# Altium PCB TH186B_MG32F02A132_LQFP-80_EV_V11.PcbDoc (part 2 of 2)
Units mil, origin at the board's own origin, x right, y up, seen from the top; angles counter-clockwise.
Board outline 4370.08 x 2637.8 mil, 2 copper layers (Top Layer, Bottom Layer); 115 components, 136 nets, 568 pads, 235 vias.

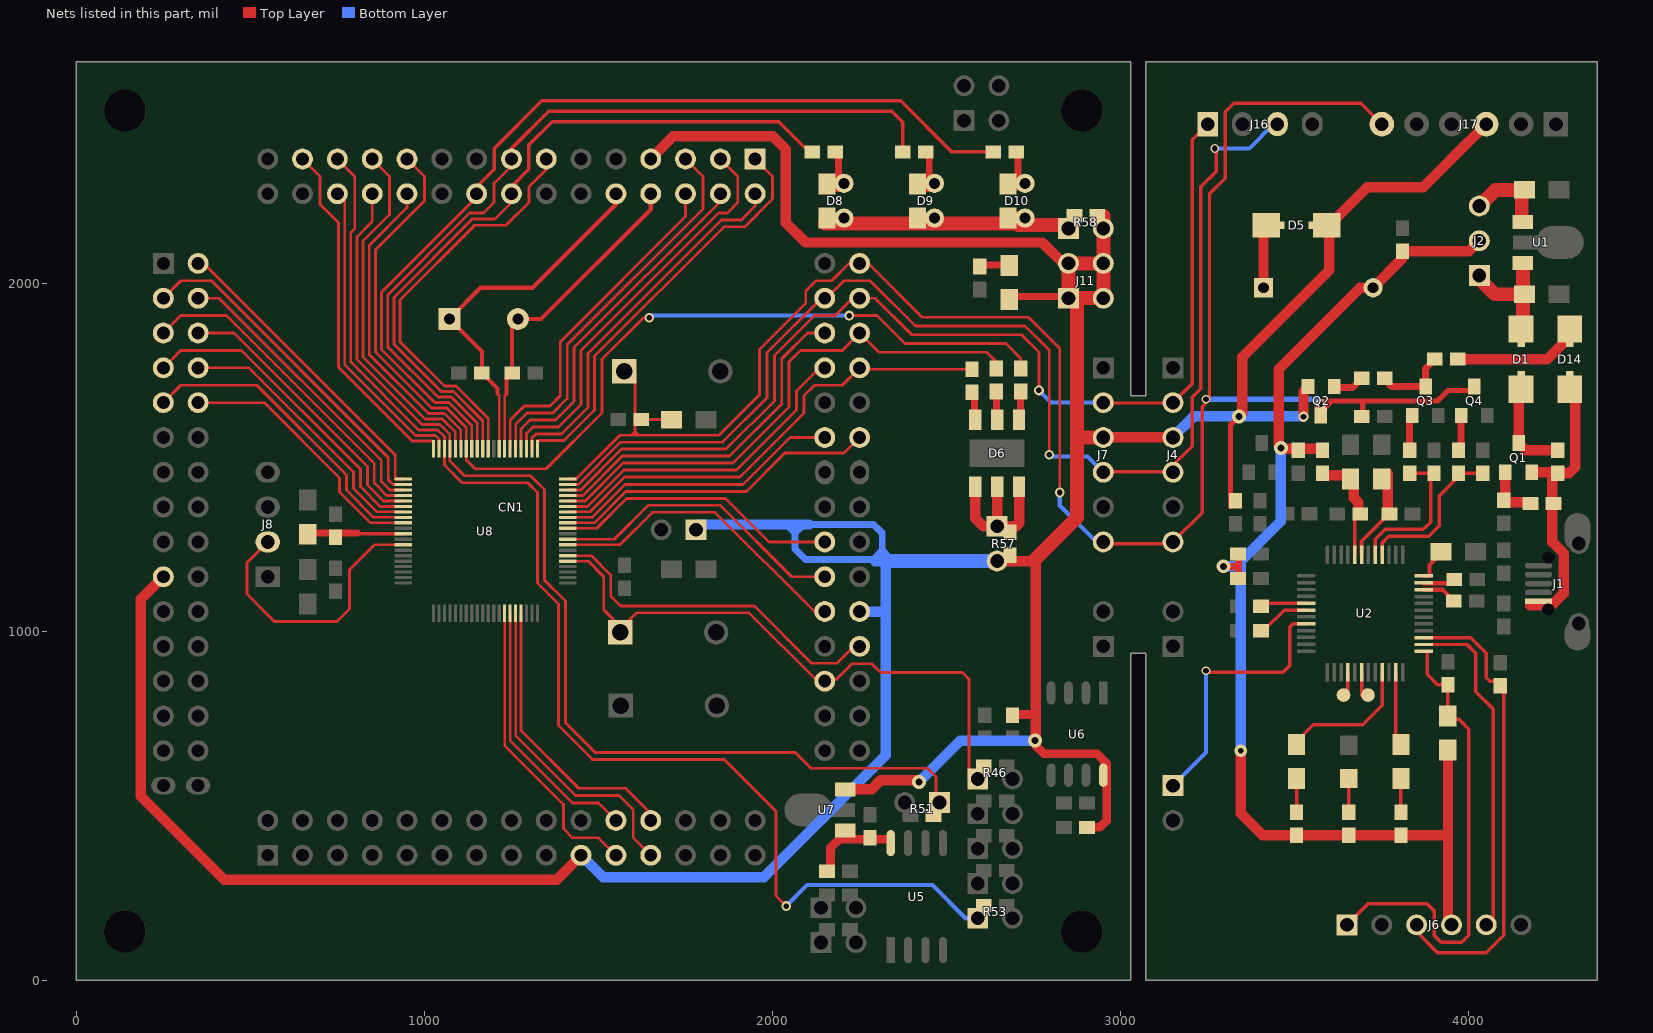
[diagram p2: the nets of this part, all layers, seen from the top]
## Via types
v1: diameter 30, hole 12, Top Layer to Bottom Layer, tented both sides, 105 vias
v2: diameter 20, hole 12, Top Layer to Bottom Layer, tented both sides, 76 vias
v3: diameter 25, hole 12, Top Layer to Bottom Layer, tented both sides, 33 vias
v4: diameter 28, hole 16, Top Layer to Bottom Layer, tented both sides, 8 vias
v5: diameter 40, hole 20, Top Layer to Bottom Layer, tented both sides, 5 vias
v6: diameter 25, hole 16, Top Layer to Bottom Layer, tented both sides, 4 vias
v7: diameter 30, hole 16, Top Layer to Bottom Layer, tented both sides, 2 vias
v8: diameter 35, hole 16, Top Layer to Bottom Layer, tented both sides, 1 vias
v9: diameter 50, hole 12, Top Layer to Bottom Layer, tented both sides, 1 vias

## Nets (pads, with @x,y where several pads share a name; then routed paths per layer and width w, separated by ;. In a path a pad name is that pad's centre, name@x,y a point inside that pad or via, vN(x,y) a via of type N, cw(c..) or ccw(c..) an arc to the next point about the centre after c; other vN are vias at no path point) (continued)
MG_PB11: CN1.36 R46.1 SW4.1 U8.25 | length 1747.4
  Top Layer w8: U8.25@1412.24,1203.35 1471.02,1203.35 1515.63,1158.74 1515.63,1063.74 SW4.1@1566.73,1012.64 ; SW4.1@1562.83,1008.74 1609.09,1055 1933.28,1055 2124.85,863.43 2150.63,863.43 2183.43,863.43 2228.74,908.74 2285.63,908.74 2310.63,883.74 2545.63,883.74 2565,864.37 R46.1@2565,580 ; 2565.06,609.31 2580.63,593.74 R46.1@2580.63,597.8 ; R46.1@2600,587.8 R46.1@2600,597.8
MG_PB12: CN1.37 U8.26 | length 1021.8
  Top Layer w8: U8.26@1412.24,1219.1 1480.28,1219.09 1535.63,1163.74 1535.63,1103.74 1564.37,1075 1948.28,1075 2113.28,910 2185,910 2233.74,958.74 CN1.37@2250.63,958.74
MG_PB13: CN1.40 U8.28 | length 895
  Top Layer w8: U8.28@1412.24,1250.59 1562.48,1250.59 1655.63,1343.74 1835.63,1343.74 2120.63,1058.74 CN1.40@2150.63,1058.74
MG_PB14: CN1.42 U8.29 | length 863.6
  Top Layer w8: U8.29@1412.24,1266.34 1545.96,1266.34 1643.36,1363.74 1850.63,1363.74 2055.63,1158.74 CN1.42@2150.63,1158.74
MG_PB15: CN1.44 U8.31 | length 825.7
  Top Layer w8: U8.31@1412.24,1297.84 1495.55,1297.83 1581.46,1383.74 1865.63,1383.74 1990.63,1258.74 CN1.44@2150.63,1258.74
MG_PC0: CN1.53 R28.1 U8.34 | length 1357.6
  Top Layer w8: U8.34@1412.24,1345.08 1475.6,1345.08 1575.72,1445.2 1907.09,1445.2 2090.63,1628.74 2090.63,1678.74 2120.63,1708.74 2200.63,1708.74 CN1.53@2250.63,1758.74 ; CN1.53@2254.63,1754.74 R28.1@2573.19,1754.74
MG_PC1: CN1.54 U8.35 | length 935.4
  Top Layer w8: U8.35@1412.24,1360.83 1469.07,1360.83 1573.44,1465.2 1897.09,1465.2 2069.42,1637.53 2069.42,1692.53 2135.63,1758.74 CN1.54@2150.63,1758.74
MG_PC2: CN1.55 R29.1 U8.36 | length 1560.4
  Top Layer w8: U8.36@1412.24,1376.58 1462.55,1376.57 1571.17,1485.2 1887.09,1485.2 2048.2,1646.31 2048.2,1776.16 2080.79,1808.74 2200.63,1808.74 CN1.55@2250.63,1858.74 2305.63,1803.74 2615.63,1803.74 2643.19,1776.18 R29.1@2643.19,1756.74
MG_PC3: CN1.56 U8.37 | length 1007.6
  Top Layer w8: U8.37@1412.24,1392.32 1456.03,1392.32 1568.9,1505.2 1877.09,1505.2 2026.99,1655.1 2026.99,1784.94 2100.79,1858.74 CN1.56@2150.63,1858.74
MG_PC7: CN1.61 U8.41 | length 1188.8
  Top Layer w8: U8.41@1325.63,1550 1401.82,1550 1489.37,1637.55 1489.37,1792.48 1860.63,2163.74 1920.63,2163.74 2000.63,2243.74 2000.63,2308.74 CN1.61@1950.63,2358.74
MG_PC8: CN1.62 U8.42 | length 1074.1
  Top Layer w8: U8.42@1309.88,1526.18 1309.88,1557.99 1320.63,1568.74 1394.06,1568.74 1470.63,1645.31 1470.63,1800.24 1854.13,2183.74 1910.63,2183.74 1950.63,2223.74 CN1.62@1950.63,2258.74
MG_PC9: CN1.63 U8.43 | length 1162
  Top Layer w8: U8.43@1294.13,1526.18 1294.13,1570.53 1312.35,1588.74 1385.78,1588.74 1450.63,1653.59 1450.63,1808.53 1845.84,2203.74 1870.63,2203.74 1900.63,2233.74 1900.63,2308.74 CN1.63@1850.63,2358.74
MG_PC10: CN1.64 U8.44 | length 1012.6
  Top Layer w8: U8.44@1278.39,1526.18 1278.39,1583.06 1304.06,1608.74 1377.49,1608.74 1430.63,1661.88 1430.63,1816.81 1850.63,2236.81 CN1.64@1850.63,2258.74
MG_PC11: CN1.65 U8.45 | length 1119.1
  Top Layer w8: U8.45@1262.64,1526.18 1262.64,1595.6 1295.78,1628.74 1369.21,1628.74 1410.63,1670.16 1410.63,1825.1 1800.63,2215.1 1800.63,2308.74 CN1.65@1750.63,2358.74
MG_PC12: CN1.66 U8.46 | length 984.2
  Top Layer w8: U8.46@1246.89,1526.18 1246.89,1608.14 1287.49,1648.74 1360.92,1648.74 1390.63,1678.45 1390.63,1833.38 1750.63,2193.38 CN1.66@1750.63,2258.74
MG_PD0: CN1.81 R30.1 U8.54 | length 3042.2
  Top Layer w8: CN1.81@950.63,2358.74 1000.63,2308.74 1000.63,2238.74 859.92,2098.03 859.92,1804.45 1021.14,1643.23 1064.77,1643.23 1120.91,1587.09 U8.54@1120.91,1526.18 1120.91,1493.46 1145.63,1468.74 1350.63,1468.74 1510.63,1628.74 1510.63,1783.74 1629.63,1902.74 v4(1646.63,1902.74) v4@1640.63,1908.74 ; v4(2220.63,1908.74) 2300.63,1908.74 2380.63,1828.74 2670.63,1828.74 2713.19,1786.18 R30.1@2713.19,1756.74
  Bottom Layer w12: v4@1652.63,1908.74 v4(2220.63,1908.74) v4@2214.63,1902.74
MG_PD1: CN1.82 U8.55 | length 913.5
  Top Layer w8: CN1.82@950.63,2258.74 950.63,2218.74 842.24,2110.35 842.24,1797.13 1011.89,1627.48 1058.25,1627.48 1105.16,1580.57 U8.55@1105.16,1526.18
MG_PD2: CN1.83 U8.56 | length 1023.2
  Top Layer w8: CN1.83@850.63,2358.74 900.63,2308.74 900.63,2198.74 824.56,2122.67 824.56,1789.81 1002.64,1611.73 1051.72,1611.73 1089.41,1574.04 U8.56@1089.41,1526.18
MG_PD3: CN1.84 R51.1 U8.57 | length 3120.1
  Top Layer w8: CN1.84@850.63,2258.74 850.63,2178.74 806.89,2135 806.89,1782.48 993.39,1595.98 1045.2,1595.98 1073.66,1567.52 U8.57@1073.66,1526.18 1073.66,1490.71 1115.63,1448.74 1305.63,1448.74 1345.63,1408.74 1345.63,1148.74 1405.63,1088.74 1405.63,739.37 1491.26,653.74 2065.63,653.74 2110.63,608.74 2445.63,608.74 2470,584.37 R51.1@2470,520
MG_PD4: CN1.85 R53.1 U8.58 | length 3678.3
  Top Layer w8: CN1.85@750.63,2358.74 800.63,2308.74 800.63,2158.74 789.21,2147.32 789.21,1775.16 984.13,1580.24 1038.68,1580.24 1057.91,1561 U8.58@1057.91,1526.18 1057.91,1479.19 1108.36,1428.74 1297.35,1428.74 1325.63,1400.46 1325.63,1140.46 1385.63,1080.46 1385.63,731.09 1482.98,633.74 1861.89,633.74 2010.63,485 2010.63,242.17 v4(2040,212.8)
  Bottom Layer w12: v4(2040,212.8) 2100,272.8 2460,272.8 2555,177.8 R53.1@2590,177.8 R53.1@2600,177.8
MG_PD5: CN1.86 U8.59 | length 886.9
  Top Layer w8: CN1.86@750.63,2258.74 771.53,2237.84 771.53,1767.84 974.88,1564.49 1032.15,1564.49 1042.17,1554.48 U8.59@1042.17,1526.18
MG_PD6: CN1.87 U8.60 | length 1023.4
  Top Layer w8: CN1.87@650.63,2358.74 700.63,2308.74 700.63,2228.74 753.85,2175.52 753.85,1760.52 965.63,1548.74 1025.63,1548.74 1026.42,1547.95 U8.60@1026.42,1526.18
MG_PD7: CN1.92 U8.61 | length 886.2
  Top Layer w8: CN1.92@350.63,2058.74 366.9,2058.74 916.8,1508.84 916.8,1439.57 U8.61@939.8,1439.57
MG_PD8: CN1.93 U8.62 | length 989.2
  Top Layer w8: CN1.93@250.63,1958.74 300.63,2008.74 388.62,2008.74 896.8,1500.56 896.8,1437.3 910.28,1423.82 U8.62@939.8,1423.82
MG_PD9: CN1.94 U8.63 | length 852.2
  Top Layer w8: CN1.94@350.63,1958.74 410.34,1958.74 876.8,1492.27 876.8,1432.57 901.3,1408.07 U8.63@939.8,1408.07
MG_PD10: CN1.95 U8.64 | length 956.8
  Top Layer w8: CN1.95@250.63,1858.74 300.63,1908.74 432.05,1908.74 856.8,1483.99 856.8,1427.57 892.05,1392.32 U8.64@939.8,1392.32
MG_PD11: CN1.96 U8.65 | length 820.1
  Top Layer w8: CN1.96@350.63,1858.74 453.77,1858.74 836.8,1475.7 836.8,1422.38 882.61,1376.57 U8.65@939.8,1376.58
MG_PD12: CN1.97 U8.66 | length 924.7
  Top Layer w8: CN1.97@250.63,1758.74 300.63,1808.74 475.48,1808.74 816.8,1467.42 816.8,1417.38 873.36,1360.83 U8.66@939.8,1360.83
MG_PD13: CN1.98 U8.67 | length 787.9
  Top Layer w8: CN1.98@350.63,1758.74 497.2,1758.74 796.8,1459.14 796.8,1412.38 864.1,1345.08 U8.67@939.8,1345.08
MG_PD14: CN1.99 U8.68 | length 892.5
  Top Layer w8: CN1.99@250.63,1658.74 300.63,1708.74 518.91,1708.74 776.8,1450.85 776.8,1407.38 854.85,1329.33 U8.68@939.8,1329.33
MG_PD15: CN1.100 U8.69 | length 755.7
  Top Layer w8: CN1.100@350.63,1658.74 540.63,1658.74 756.8,1442.57 756.8,1402.38 845.6,1313.58 U8.69@939.8,1313.58
MG_PE0: CN1.21 U8.14 | length 870.9
  Top Layer w8: U8.14@1231.14,1053.74 1231.14,673.86 1400,505 1400,435 1426.26,408.74 1500.63,408.74 CN1.21@1550.63,358.74
MG_PE1: CN1.22 U8.15 | length 764.4
  Top Layer w8: U8.15@1246.89,1053.74 1246.89,688.11 1426.26,508.74 1500.63,508.74 CN1.22@1550.63,458.74
MG_PE2: CN1.23 U8.16 | length 928.6
  Top Layer w8: U8.16@1262.64,1053.74 1262.64,702.36 1435.05,529.95 1559.42,529.95 1600.63,488.74 1600.63,408.74 CN1.23@1650.63,358.74
MG_PE3: CN1.24 U8.17 | length 827.9
  Top Layer w8: U8.17@1278.39,1053.74 1278.39,716.61 1443.83,551.17 1578.2,551.17 1650.63,478.74 CN1.24@1650.63,458.74
MG_PE8: CN1.49 U8.32 | length 939.9
  Top Layer w8: U8.32@1412.24,1313.58 1488.64,1313.58 1578.8,1403.74 1925.63,1403.74 2035.63,1513.74 2205.63,1513.74 CN1.49@2250.63,1558.74
MG_PE9: CN1.50 U8.33 | length 833.4
  Top Layer w8: U8.33@1412.24,1329.33 1482.12,1329.33 1576.53,1423.74 1915.63,1423.74 2050.63,1558.74 CN1.50@2150.63,1558.74
MG_PE12: CN1.73 U8.50 | length 1183.3
  Top Layer w8: U8.50@1183.9,1526.18 1183.9,1613.18 1090.86,1706.22 1058.15,1706.22 930.63,1833.74 930.63,1953.74 1145.28,2168.38 1235.27,2168.38 1300.63,2233.74 1300.63,2278.74 1350.63,2328.74 CN1.73@1350.63,2358.74
MG_PE13: CN1.76 R54.1 U8.51 | length 2082.7
  Top Layer w8: U8.51@1168.15,1526.18 1168.15,1606.66 1084.34,1690.47 1048.9,1690.47 912.95,1826.42 912.95,1961.06 1137.95,2186.06 1202.95,2186.06 1250.63,2233.74 CN1.76@1250.63,2258.74
  Top Layer w10: CN1.76@1250.63,2258.74 1250.63,2278.74 1300.63,2328.74 1300.63,2398.74 1367.51,2465.62 2018.75,2465.62 2093.13,2391.24 2114.63,2391.24 R54.1@2127.13,2391.24
MG_PE14: CN1.75 R55.1 U8.52 | length 2428.8
  Top Layer w8: U8.52@1152.4,1526.18 1152.4,1600.14 1077.81,1674.72 1039.65,1674.72 895.27,1819.1 895.27,1968.39 1130.63,2203.74 1170.63,2203.74 1200.63,2233.74 1200.63,2288.74 1250.63,2338.74 CN1.75@1250.63,2358.74
  Top Layer w10: CN1.75@1250.63,2358.74 1250.63,2388.74 1357.51,2495.62 2343.16,2495.62 2374.63,2464.15 R55.1@2374.63,2378.74
MG_PE15: CN1.78 R56.1 U8.53 | length 2679.2
  Top Layer w8: U8.53@1136.65,1526.18 1136.65,1593.61 1071.29,1658.98 1030.39,1658.98 877.6,1811.77 877.6,1975.71 1150.63,2248.74 CN1.78@1150.63,2258.74 CN1.78@1150.63,2278.74
  Top Layer w10: CN1.78@1150.63,2278.74 1200.63,2328.74 1200.63,2388.74 1337.51,2525.62 2368.75,2525.62 2515.63,2378.74 R56.1@2634.63,2378.74
MG_VR0X: C15.1 C17.1 U8.71 | length 269.8
  Top Layer w9: 808.98,1282.09 U8.71@939.8,1282.09
  Top Layer w20: C15.1@670,1283.74 745,1283.74 808.98,1283.74
NetC2_2: C2.2 Q1.1 R5.2 | length 157.6
  Top Layer w30: R5.2@4105,1373 C2.2@4177.63,1373 ; R5.2@4105.63,1378.74 Q1.1@4105.63,1458.74 Q1.1@4105.63,1463.74
NetC6_1: C6.1 C7.2 R10.2 U2.44 | length 292.2
  Top Layer w11: U2.44@3672.82,1221.87 C7.2@3672.82,1338.74
  Top Layer w30: R10.2@3595,1450 C6.1@3659.96,1450 ; C6.1@3660.59,1439.53 3670,1430.12 3670,1385 3683.63,1371.37 C7.2@3683.63,1338.74
NetC8_2: C8.2 C9.1 U2.43 | length 262.1
  Top Layer w11: U2.43@3692.51,1221.87 3692.51,1260.62 3757.63,1325.74 C8.2@3757.63,1338.74
  Top Layer w30: C8.2@3767.63,1336.74 3767.63,1338.74 3767.63,1439.53 C9.1@3767.63,1455
NetC11_1: C11.1 U2.36 | length 80
  Top Layer w12: U2.36@3871.09,1160.9 3887.79,1160.9 3887.79,1192.79 C11.1@3910,1215
NetD1_1: D1.1 Q1.3 R1.2 | length 275.1
  Top Layer w30: D1.1@4143.63,1697.13 Q1.3@4143.63,1542.68 4164.57,1521.74 R1.2@4255.63,1521.74
NetD2_1: D2.1 R6.2 | length 97
  Top Layer w10: R6.2@3505.63,481.74 D2.1@3505.63,578.74
NetD3_1: D3.1 R9.2 | length 97
  Top Layer w10: R9.2@3805.63,481.74 D3.1@3805.63,578.74
NetD4_1: D4.1 R11.2 | length 97
  Top Layer w10: R11.2@3655.63,481.74 D4.1@3655.63,578.74
NetD5_1: D5.1 SW1.1 | length 179.1
  Top Layer w30: SW1.1@3410.67,1988.74 D5.1@3410.67,2167.87
NetD6_1: D6.1 D6.3 D6.5 R57.1 | length 448.5
  Top Layer w30: D6.1@2582.64,1417.28 2582.64,1326.73 2605.63,1303.74 R57.1@2645.63,1303.74 ; D6.3@2645.63,1417.28 R57.1@2645.63,1303.74 ; D6.5@2708.62,1417.28 2708.62,1311.73 2700.63,1303.74 2682.48,1303.74 R57.1@2645.63,1303.74
NetD6_2: D6.2 R28.2 | length 78.5
  Top Layer w20: D6.2@2580.63,1610.2 R28.2@2580.63,1688.74
NetD6_4: D6.4 R29.2 | length 80.5
  Top Layer w20: D6.4@2643.19,1610.2 R29.2@2643.19,1690.74
NetD6_6: D6.6 R30.2 | length 80.5
  Top Layer w20: D6.6@2713.19,1610.2 R30.2@2713.19,1690.74
NetD7_2: D7.2 R31.2 | length 85
  Top Layer w20: R31.2@2595.63,2053.74 D7.2@2680.63,2053.74
NetD8_1: D8.1 D9.1 D10.1 R58.1 | length 756.8
  Top Layer w40: D8.1@2150.63,2173.74 2156.95,2173.74 2205.63,2173.74 2416.95,2173.74 2465.63,2173.74 2676.95,2173.74 D10.1@2713.78,2173.74 ; D10.1@2676.95,2188.74 D10.1@2725.63,2188.74 ; 2705.63,2168.74 2725.63,2168.74 R58.1@2850.63,2168.74
NetD8_2: D8.2 R54.2 | length 138.7
  Top Layer w20: D8.2@2156.95,2273.74 D8.2@2205.63,2273.74 ; D8.2@2190.63,2288.74 R54.2@2190.63,2378.74
NetD9_2: D9.2 R55.2 | length 138.7
  Top Layer w20: D9.2@2416.95,2273.74 D9.2@2465.63,2273.74 ; D9.2@2450.63,2283.74 2450.63,2287.29 2450.63,2288.74 R55.2@2450.63,2373.74
NetD10_2: D10.2 R56.2 | length 148.7
  Top Layer w20: D10.2@2676.95,2278.74 D10.2@2705.63,2278.74 ; R56.2@2705.63,2368.74 2705.63,2288.74 2705.63,2287.29 D10.2@2705.63,2278.74 ; D10.2@2735.63,2278.74 2725.63,2278.74 D10.2@2705.63,2278.74
NetD14_2: D14.2 R17.1 | length 348.7
  Top Layer w30: R17.1@3968.59,1783.74 4220.59,1783.74 ; 4225.59,1783.74 D14.2@4284.67,1842.81 ; D14.2@4273.74,1866.89 D14.2@4285.59,1866.89 ; D14.2@4279.67,1842.81 D14.2@4280.59,1843.74
NetQ2_1: Q2.1 R18.2 | length 89.8
  Top Layer w20: Q2.1@3613.59,1702.68 3666.57,1702.68 R18.2@3692.63,1728.74
NetQ3_1: Q3.1 R19.2 | length 120.2
  Top Layer w20: R19.2@3830.63,1538.78 R19.2@3830.63,1521.74 3830.63,1614.27 Q3.1@3838.13,1621.77
NetQ3_2: Q3.2 R17.2 R18.1 | length 192.7
  Top Layer w20: R18.1@3763.63,1728.74 3763.63,1720.7 3778.62,1705.71 Q3.2@3876.13,1705.71 ; 3876.13,1728.74 3876.13,1757.28 R17.2@3902.59,1783.74
NetQ4_1: Q4.1 R23.2 | length 92.5
  Top Layer w20: R23.2@3978.13,1529.24 Q4.1@3978.13,1621.77
NetR15_1: R15.1 U2.35 | length 108.8
  Top Layer w12: U2.35@3871.09,1140.21 3900.63,1140.21 ; 3932.89,1140.21 3900.63,1140.21 ; R15.1@3947.63,1140.21 3900.63,1140.21
NetR16_1: R16.1 U2.34 | length 100.1
  Top Layer w12: U2.34@3871.09,1121.53 3924.84,1121.53 R16.1@3957.63,1088.74
NetTP1_1: TP1.1 U2.16 | length 97.8
  Top Layer w10: TP1.1@3653.14,818.74 U2.16@3653.14,884.39 3653.14,852.25
NetTP2_1: TP2.1 U2.18 | length 65.6
  Top Layer w10: TP2.1@3692.51,818.74 U2.18@3692.51,884.39
P44: J6.5 U2.26 | length 969
  Top Layer w10: U2.26@3871.09,964.05 3995.32,964.05 4020.63,938.74 4020.63,828.74 4070.63,778.74 4070.63,178.74 J6.5@4050.63,158.74
P45: J6.3 R25.1 U2.27 | length 1354.4
  Top Layer w10: J6.3@3850.63,158.74 3850.63,138.74 3910.63,78.74 4050.63,78.74 4100.63,128.74 4100.63,835.74 R25.1@4090.63,845.74 4077.63,858.74 4060.63,858.74 4050.63,868.74 4050.63,938.74 4005.64,983.73 U2.27@3871.09,983.73
PASS: D3.2 U2.23 | length 191.9
  Top Layer w10: D3.2@3790.93,692.47 U2.23@3790.93,884.39
RST: C12.2 J6.1 R22.2 U2.25 | length 1353.4
  Top Layer w10: J6.1@3650.63,158.74 3710.63,218.74 3880.63,218.74 3900.63,198.74 3900.63,128.74 3920.63,108.74 3980.63,108.74 4000.63,128.74 4000.63,720.64 3972.53,748.74 C12.2@3945.53,748.74 ; U2.25@3880.63,944.36 3880.63,878.74 3910.63,848.74 R22.2@3940.63,848.74 C12.2@3940.63,761.74
RST/MG_PC6: C13.2 CN1.59 J4.6 J7.6 J17.6 Q2.3 Q4.2 R21.1 R27.2 SW2.1 U8.40 | length 5985.2
  Top Layer w8: SW2.1@1605.53,1738.74 R27.2@1605.53,1618.74 ; R27.2@1621.56,1610 1623,1610 C13.2@1685.53,1610 ; R27.2@1623,1618.74 R27.2@1605.53,1618.74 ; v4(2825.63,1400.64) 2825.63,1814.45 2736.34,1903.74 2430.63,1903.74 2275.63,2058.74 CN1.59@2250.63,2058.74 2220.63,2058.74 2170.63,2008.74 2125.63,2008.74 2095.63,1978.74 2095.63,1943.58 1963.35,1811.3 1963.35,1681.46 1847.09,1565.2 1615.33,1565.2 ; U8.40@1436.46,1439.57 U8.40@1412.24,1439.57 U8.40@1436.46,1439.57 ; U8.40@1436.46,1439.57 1562.09,1565.2 1595.73,1565.2 ; 1595.73,1565.2 1605.53,1575 ; 1595.73,1565.2 1605.53,1565.2 ; 1605.53,1565.2 1615.33,1565.2 ; 1605.53,1565.2 1605.53,1575 ; 1605.53,1575 1605.53,1610.64 R27.2@1605.53,1618.74 ; 1605.53,1575 1615.33,1565.2
  Top Layer w10: J7.6@2950.63,1253.74 J4.6@3150.63,1253.74 ; J4.6@3150.63,1252.74 J4.6@3151.63,1252.74 ; J4.6@3150.63,1258.74 3234.38,1342.49 3234.38,1647.49 3250.63,1663.74 3255.63,1668.74 3255.63,1803.74 ; 3255.63,1913.74 3255.63,1803.74 ; 3255.63,2228.74 3255.63,2058.74 ; J17.6@3750.63,2458.74 3690.63,2518.74 3325.63,2518.74 3300.63,2493.74 3300.63,2303.74 3255.63,2258.74 3255.63,2058.74 ; 3255.63,1803.74 3255.63,2058.74
  Top Layer w15: v7@3565,1645 v7(3575.59,1653.74) 3585.59,1663.74 3605.59,1663.74 ; Q2.3@3575.59,1633.74 Q2.3@3580.59,1638.74 ; Q2.3@3580.59,1613.74 3580.59,1621.77 Q2.3@3580.59,1638.74 ; R21.1@3695.59,1620.74 3695.59,1663.74 ; Q4.2@4006.22,1693.74 3940.59,1693.74 3910.59,1663.74 3695.59,1663.74 ; Q2.3@3580.59,1638.74 3585.59,1643.74 3605.59,1663.74 ; 3605.59,1663.74 3695.59,1663.74
  Bottom Layer w12: v4@2825.53,1398.74 2825.53,1363.84 2940.63,1248.74 J7.6@2950.63,1238.74
  Bottom Layer w15: v6(3245.63,1668.74) 3560.59,1668.74 v7(3575.59,1653.74) v7@3565.59,1663.74
RST_CTRL_51: R19.1 R20.1 U2.41 | length 433.5
  Top Layer w10: U2.41@3731.88,1221.87 3731.88,1265.99 3760.89,1295 3870,1295 3890.63,1315.63 R20.1@3890.63,1455.74 ; R19.1@3830.63,1455.74 R20.1@3890.63,1455.74 ; R20.1@3900.63,1455.74 R20.1@3890.63,1455.74
RST_CTRL_ARM: R23.1 R24.1 U2.40 | length 461.5
  Top Layer w10: U2.40@3751.56,1221.87 3751.56,1255.67 3770.89,1275 3885,1275 3915.63,1305.63 3915.63,1390.63 3970.63,1445.63 R23.1@3970.63,1455.74 R24.1@4040.63,1455.74
SWCLK/MG_PC4: CN1.57 J4.2 J7.2 J16.1 U8.38 | length 3093.9
  Top Layer w8: U8.38@1412.24,1408.07 1449.5,1408.07 1566.63,1525.2 1867.09,1525.2 2005.78,1663.89 2005.78,1793.73 2120.79,1908.74 2180.63,1908.74 2230.63,1958.74 CN1.57@2250.63,1958.74 2295.27,1958.74 2400.27,1853.74 2715.63,1853.74 2765.63,1803.74 v4(2765.63,1693.74)
  Top Layer w10: J7.2@2950.63,1657.74 J4.2@3150.63,1657.74 ; J4.2@3150.63,1658.74 3205.63,1713.74 3205.63,2413.74 J16.1@3250.63,2458.74
  Bottom Layer w12: v4(2765.63,1693.74) 2800.63,1658.74 J7.2@2950.63,1658.74 J7.2@2935.63,1673.74
SWDIO/MG_PC5: CN1.58 J4.4 J7.4 J16.3 U8.39 | length 3664.8
  Top Layer w8: U8.39@1412.24,1423.82 1442.98,1423.82 1564.36,1545.2 1857.09,1545.2 1984.56,1672.67 1984.56,1802.52 2140.79,1958.74 CN1.58@2150.63,1958.74 2155.63,1958.74 2205.63,2008.74 2280.63,2008.74 2410.63,1878.74 2725.99,1878.74 2795.63,1809.1 v4(2795.63,1508.74) v4@2795.63,1503.74
  Top Layer w10: J7.4@2950.63,1459.74 J4.4@3136.63,1459.74 ; J4.4@3150.63,1458.74 3135.63,1458.74 J4.4@3136.63,1459.74 ; v6@3275.63,2388.74 3275.63,2323.74 3230.63,2278.74 3230.63,1698.74 3205.63,1673.74 3205.63,1533.74 3143.13,1471.24 3143.13,1466.24 J4.4@3136.63,1459.74
  Top Layer w12: J7.4@2948.98,1459.74 J7.4@2950.63,1459.74 ; J4.4@3136.63,1459.74 J4.4@3148.98,1459.74
  Bottom Layer w12: v4@2795.63,1503.74 2905.63,1503.74 J7.4@2950.63,1458.74 ; v6(3270.63,2388.74) 3370,2388.74 J16.3@3440,2458.74
TOOL_OPTION0: R2.1 U2.5 | length 123.2
  Top Layer w10: R2.1@3413.63,1073.74 3422.55,1082.66 U2.5@3533.11,1082.66
TOOL_OPTION1: R3.1 U2.6 | length 141.9
  Top Layer w10: R3.1@3413.63,1003.74 R3.1@3415.63,1003.74 ; R3.1@3415.63,1008.74 3469.86,1062.97 U2.6@3533.11,1062.97
USBOK: D2.2 U2.21 | length 377.6
  Top Layer w10: D2.2@3510,690 3553.74,733.74 3695.63,733.74 3751.56,789.67 U2.21@3751.56,884.39
VCC3: C20.1 R32.2 U5.8 U7.1 | length 245.6
  Top Layer w25: R32.2@2167,317.8 2167,380.11 2191.89,405 2210,405 2280.63,405 U5.8@2340,405
VCC_USB: C2.1 D14.1 J1.1 Q1.2 R1.1 | length 826.7
  Top Layer w30: 4177.28,1076.22 4200.63,1076.22 4228.19,1076.22 4238.07,1076.22 4273.07,1111.22 4273.07,1226.22 4243.07,1256.22 ; Q1.2@4180.63,1458.74 R1.1@4252.63,1458.74 ; 4240.51,1257.56 4240.51,1368.74 R1.1@4240.51,1453.74 ; R1.1@4245.63,1455.74 R1.1@4255.63,1455.74 4287.59,1455.74 4305.59,1473.74 D14.1@4305.59,1697.13
VCP_OPTION: J3.1 U2.8 | length 939.2
  Top Layer w10: v6@3245.63,883.74 3465.63,883.74 ; 3300.63,883.74 3465.63,883.74 ; U2.8@3533.11,1023.6 3495.49,1023.6 3485.63,1013.74 3485.63,903.74 3465.63,883.74
  Bottom Layer w12: J3.1@3150.63,558.74 3245.63,653.74 v6@3245.63,883.74
  other v6: 3245.63,888.74
VDD: C12.1 J2.2 J6.4 R4.1 R6.1 R9.1 R10.1 R11.1 R12.1 R13.1 R14.2 SW1.2 | length 3450.8
  Top Layer w20: v5(3295.63,1188.74) 3329.56,1188.74 ; R12.1@3339.63,1153.74 R13.1@3339.63,1223.3
  Top Layer w30: v8@3345.63,658.74 3345.63,478.74 3408.63,415.74 R6.1@3505.63,415.74 R11.1@3655.63,415.74 R9.1@3805.63,415.74 3940.63,415.74 ; v5(3460.59,1528.74) 3455,1534.33 3455,1755 3688.74,1988.74 SW1.2@3725.63,1988.74 3810,2073.11 R4.1@3810,2094 4000.89,2094 J2.2@4030.63,2123.74 ; v5@3467.59,1526.74 3510.59,1526.74 R14.2@3515.59,1526.74 ; R14.2@3520.59,1526.74 R10.1@3580,1526.74 ; J6.4@3940.63,158.74 3940.63,415.74 ; C12.1@3940.63,660.79 3940.63,415.74
  Bottom Layer w30: v5(3295.63,1188.74) 3345.63,1188.74 ; v8@3345.63,658.74 3345.63,1188.74 ; v5(3460.59,1528.74) 3460.59,1318.7 3345.63,1203.74 3345.63,1188.74
  other v8: 3345.53,658.74
VDD3: C5.1 J2.3 U1.1 | length 229.3
  Top Layer w40: J2.3@4030.63,2223.74 4076.89,2270 C5.1@4152.59,2270 ; U1.1@4152.59,2193.74 C5.1@4152.59,2270 ; C5.1@4152.59,2273.74 C5.1@4152.59,2270 ; C5.1@4160.79,2270 C5.1@4152.59,2270
VDD5: C4.1 D1.2 J2.1 U1.3 | length 301.2
  Top Layer w40: J2.1@4035.83,2010 4075.83,1970 C4.1@4155.59,1970 ; D1.2@4155.59,1900.35 C4.1@4155.59,1970 ; U1.3@4155.59,2060 C4.1@4155.59,1970 ; C4.1@4160.79,1970 C4.1@4155.59,1970
VDUT: CN1.19 CN1.39 CN1.67 CN1.109 D5.2 D7.1 J4.3 J7.3 J11.1 J11.2 J11.3 J11.4 J17.3 J18.1 Q2.2 R7.1 R44.1 R45.1 R57.2 R58.2 U6.8 U7.3 | length 12334.1
  Top Layer w15: R7.1@3315.63,1360.74 3315.63,1376.74 R7.1@3315.63,1395.74 ; R7.1@3337.63,1373.74 3332.63,1378.74 R7.1@3315.63,1395.74 ; v5(3340.63,1619.24) 3315.63,1594.24 R7.1@3315.63,1395.74
  Top Layer w20: D7.1@2680.63,1963.74 J11.1@2850.63,1963.74
  Top Layer w25: R44.1@2690,763.24 2756.63,763.24 ; v5@2756.63,687.8 2756.63,673.37 2780,650 2932.48,650 2960.63,621.85 2960.63,588.74 2960.63,458.74 2940.63,438.74 R45.1@2903.63,438.74
  Top Layer w30: CN1.109@250.63,1158.74 185.63,1093.74 185.63,528.74 425.63,288.74 1380.63,288.74 CN1.19@1450.63,358.74 ; CN1.67@1650.63,2358.74 1715.63,2423.74 2000.63,2423.74 2038.29,2386.08 2038.29,2176.08 2095.63,2118.74 2775.04,2118.74 J11.2@2835.04,2058.74 ; U7.3@2210,548.11 2285,548.11 2310.63,573.74 v5@2420.63,573.74 ; R57.2@2645.63,1203.74 2682.48,1203.74 2750.63,1203.74 ; v5@2756.63,687.8 2756.63,763.24 2756.63,1199.06 ; J7.3@2950.63,1558.74 J4.3@3150.63,1558.74 ; v5(3340.63,1619.24) 3350,1628.61 3350,1789.47 3599.72,2039.19 3599.72,2168.74 3708.93,2277.95 3869.84,2277.95 J17.3@4050.63,2458.74 3950.63,2358.74 ; v7@3525.59,1619.24 3525.59,1689.68 Q2.2@3538.59,1702.68
  Top Layer w40: 2750.63,1203.74 2875.63,1328.74 2875.63,1558.74 ; J7.3@2950.63,1558.74 2875.63,1558.74 ; R58.2@2950.63,2195.59 R58.2@2950.63,2158.74 J11.4@2950.63,2058.74 ; 2875.63,1558.74 J11.1@2875.63,1958.74 ; J11.1@2875.63,1958.74 J11.1@2850.63,1958.74 2850.63,1963.74 J11.2@2850.63,2058.74 J11.4@2950.63,2058.74 ; J11.1@2875.63,1958.74 J11.3@2950.63,1958.74 J11.4@2950.63,2058.74
  Bottom Layer w20: 2040.63,1308.74 2065.63,1283.74 ; 2065.63,1308.74 2065.63,1283.74 ; 2090.63,1308.74 2065.63,1283.74 ; 2105.63,1308.74 2290.63,1308.74 2315.63,1283.74 2315.63,1233.74 ; 2340.63,1208.74 2315.63,1233.74 ; 2065.63,1283.74 2065.63,1238.74 2095.63,1208.74 2290.63,1208.74 2315.63,1233.74
  Bottom Layer w30: CN1.19@1450.63,358.74 1514.37,295 1975,295 2325.63,645.63 2325.63,1058.74 ; J18.1@1785.63,1308.74 2040.63,1308.74 2065.63,1308.74 2090.63,1308.74 2105.63,1308.74 ; CN1.39@2250.63,1058.74 2325.63,1058.74 ; 2295.63,1203.74 2325.63,1203.74 ; 2310.63,1213.74 2325.63,1213.74 2325.63,1203.74 ; v5(2420.63,568.74) 2539.69,687.8 v5(2755,687.8) v5@2756.63,687.8 ; J4.3@3150.63,1558.74 3211.13,1619.24 v5(3340.63,1619.24) v7@3525.59,1619.24 ; 2325.63,1058.74 2325.63,1203.74
  Bottom Layer w40: 2325.63,1203.74 R57.2@2645.63,1203.74
  other v7: 3525.59,1618.74
VREF+: J8.2 U8.73 | length 814.3
  Top Layer w8: J8.2@550.63,1258.74 490.63,1198.74 490.63,1108.74 569.37,1030 750,1030 785.63,1065.63 785.63,1178.74 857.48,1250.59 U8.73@939.8,1250.59
XIN/MG_PC13: C19.1 CN1.68 U8.47 X1.2 | length 945.3
  Top Layer w8: U8.47@1231.14,1526.18 1231.14,1678.74 1236.14,1683.74
  Top Layer w12: 1236.14,1683.74 1236.14,1727.25 C19.1@1252.63,1743.74 1252.63,1882.32 X1.2@1269.05,1898.74 1335.63,1898.74 1650.63,2213.74 CN1.68@1650.63,2258.74
XOUT/MG_PC14: C18.1 CN1.70 U8.48 X1.1 | length 1077
  Top Layer w8: 1210.39,1683.74 1215.39,1678.74 U8.48@1215.39,1526.18
  Top Layer w12: 1210.39,1683.74 1210.39,1698.98 C18.1@1165.63,1743.74 1165.63,1805.32 X1.1@1072.2,1898.74 1162.2,1988.74 1310.63,1988.74 1550.63,2228.74 CN1.70@1550.63,2258.74
pads on no net: CN1.1 CN1.15 CN1.16 CN1.18 CN1.20 CN1.25 CN1.26 CN1.30 CN1.31 CN1.38 CN1.43 CN1.45 CN1.46 CN1.47 CN1.48 CN1.51 CN1.52 CN1.60 CN1.71 CN1.72 CN1.74 CN1.77 CN1.79 CN1.80 CN1.88 CN1.89 CN1.90 CN1.91 CN1.101 CN1.102 CN1.103 CN1.104 CN1.105 CN1.106 CN1.108 CN1.110 CN1.111 CN1.112 CN1.113 CN1.121 CN1.122 D6.0 J1.0 J6.6 J7.1 J8.4 U2.1 U2.2 U2.3 U2.4 U2.7 U2.9 U2.10 U2.11 U2.12 U2.15 U2.17 U2.19 U2.20 U2.24 U2.28 U2.29 U2.30 U2.32 U2.37 U2.38 U2.39 U2.46

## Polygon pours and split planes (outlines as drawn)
GND_POWER on Bottom Layer "Top Layer-No Net" (hatched 90Degree grid 10 track 10, remove dead copper, pour order 1001): 30.63,28.74 4340.63,28.74 4340.63,2608.74 30.63,2608.74
GND_POWER on Top Layer "Top Layer-No Net" (hatched 90Degree grid 10 track 10, remove dead copper, pour order 1001): 30.63,28.74 4340.63,28.74 4340.63,2608.74 30.63,2608.74

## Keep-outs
Keep-Out Layer:
  circle w7.88: c2888.98,140 r122.58
  circle w7.88: c140,140 r122.58
  circle w7.88: c2888.98,2497.8 r122.58
  circle w7.88: c140,2497.8 r122.58

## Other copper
Top Layer:
  pour cut-out: 2990.63,2637.8 3110.63,2637.8 3110.63,-1.26 2990.63,-1.26
Bottom Layer:
  pour cut-out: 2990.63,2637.8 3110.63,2637.8 3110.63,-1.26 2990.63,-1.26

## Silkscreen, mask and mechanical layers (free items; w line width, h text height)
Top Overlay:
  circle w10: c2888.98,140 r120
  circle w10: c140,140 r120
  circle w10: c140,2497.8 r120
  circle w10: c2888.98,2497.8 r120
  lines w10: 445.53,1423.74 445.53,1405.11 486.9,1363.74 495.53,1363.74 ; 470,1263.74 495.53,1263.74
  lines w15: 2025.63,2130.64 2025.63,2608.74 1700.63,2608.74 1700.63,2308.74 1500.63,2308.74 1500.63,1988.74 1920.63,1988.74 1920.63,1708.74 2470.63,1708.74 2470.63,2128.74 ; 1000.63,98.74 1200.63,98.74 1200.63,718.74 1000.63,718.74 ; 1000.63,98.74 0.63,98.74 0.63,1008.74 575.63,1008.74 575.63,718.74 1000.63,718.74 ; 1000.63,98.74 1000.63,718.74 ; 2470.63,2128.74 2025.63,2128.74 2470.63,2128.74 ; 0.63,1608.74 0.63,2608.74 1000.63,2608.74 1000.63,2028.74 620.63,2028.74 620.63,1608.74 0.63,1608.74 ; 1500.63,98.74 1700.63,98.74 1700.63,678.74 1500.63,678.74 1500.63,98.74 ; 1800.63,98.74 2010.63,98.74 2010.63,583.74 2500.63,583.74 2500.63,1008.74 2200.63,1008.74 2200.63,1308.74 1890.63,1308.74 1890.63,678.74 1800.63,678.74 1800.63,98.74
  text "GND" at 2355.63,2558.74 h50
  text "PC7" at 1980.63,2448.74 h50 r90
  text "PD6" at 670.63,2428.74 h50 r90
  text "PD4" at 770.63,2428.74 h50 r90
  text "PD2" at 870.63,2428.74 h50 r90
  text "PD0" at 980.63,2428.74 h50 r90
  text "PE14" at 1280.63,2428.74 h50 r90
  text "PE12" at 1390.63,2428.74 h50 r90
  text "GND" at 1570.63,2428.74 h50 r90
  text "VDUT" at 1670.63,2428.74 h50 r90
  text "PC11" at 1780.63,2428.74 h50 r90
  text "PC9" at 1880.63,2428.74 h50 r90
  text "When J16 Open," at 3125.63,2333.74 h45
  text "SCL" at 4170.63,2318.74 h35 r90
  text "CLK" at 4270.63,2318.74 h35 r90
  text "RST" at 3770.63,2308.74 h37 r90
  text "GND" at 3870.63,2303.74 h37 r90
  text "SDA" at 3970.63,2303.74 h37 r90
  text "VCC" at 4070.63,2303.74 h37 r90
  text "SW1 must be off." at 3125.63,2258.74 h45
  text "VDD3" at 3845.63,2198.74 h37
  text "PE13" at 2105.63,2158.74 h50 r90
  text "PE14" at 2365.63,2158.74 h50 r90
  text "PE15" at 2625.63,2158.74 h50 r90
  text "VDD" at 3865.63,2108.74 h37
  text "PD5" at 780.63,2058.74 h50 r90
  text "PD3" at 880.63,2058.74 h50 r90
  text "PD1" at 970.63,2058.74 h50 r90
  text "PC8" at 1970.63,2058.74 h50 r90
  text "PC6" at 2320.63,2038.74 h50
  text "PD7" at 420.63,2028.74 h50
  text "PE15" at 1180.63,2018.74 h50 r90
  text "PE13" at 1280.63,2018.74 h50 r90
  text "PC14" at 1580.63,2018.74 h50 r90
  text "PC13" at 1670.63,2018.74 h50 r90
  text "PC12" at 1770.63,2018.74 h50 r90
  text "PC10" at 1870.63,2018.74 h50 r90
  text "VDD5" at 3845.63,2008.74 h37
  text "PD8" at 60.63,1938.74 h50
  text "PC5" at 1950.63,1938.74 h50
  text "PC4" at 2320.63,1938.74 h50
  text "PD9" at 420.63,1928.74 h50
  text "Power" at 2510,1860.64 h50
  text "Power Off" at 3230.63,1843 h45
  text "VDUT" at 2825,1840.64 h50
  text "PD10" at 25.51,1838.74 h50
  text "PC3" at 1950.63,1838.74 h50
  text "PC2" at 2320.63,1838.74 h50
  text "PD11" at 420.63,1828.74 h50
  text "PC1" at 1950.63,1738.74 h50
  text "PC0" at 2320.63,1738.74 h50
  text "PD12" at 20.63,1728.74 h50
  text "PD13" at 420.63,1728.74 h50
  text "RESET" at 1525.53,1665 h50 r90
  text "PD14" at 20.63,1628.74 h50
  text "PD15" at 420.63,1628.74 h50
  text "SCL" at 2760.63,1623.74 h45
  text "PE9" at 1950.63,1538.74 h50
  text "VDUT" at 2745.53,1533.74 h45
  text "PE8" at 2320.63,1528.74 h50
  text "U8 current" at 1570.72,1440.21 h45
  text "GND" at 475.53,1438.74 h50 r90
  text "SDA" at 2760.63,1438.74 h45
  text "measurement" at 1570.63,1378.74 h45
  text "GND" at 2760.63,1338.74 h45
  text "RST" at 2760.63,1238.74 h45
  text "GND" at 60.63,1228.74 h50
  text "PB15" at 1910.63,1228.74 h50
  text "VREF" at 465.53,1200 h50 r90
  text "PB14" at 1910.63,1128.74 h50
  text "GND" at 2320.63,1128.74 h50
  text "VDUT" at 20.63,1113.74 h50
  text "PB8_TX" at 2605.53,1075 h50
  text "↓" at 3270.63,1058.74 h110 r90
  text "VDD" at 490,1040 h50 r90
  text "↓" at 2880.63,1038.74 h110 r90
  text "PB13" at 1910.63,1028.74 h50
  text "VDUT" at 2320.63,1028.74 h50
  text "↓" at 2830.63,978.74 h110 r270
  text "↓" at 3220.63,958.74 h110 r270
  text "PB11" at 1510,950 h50 r90
  text "PA0" at 420.63,928.74 h50
  text "PB12" at 2320.63,928.74 h50
  text "PB9_RX" at 2605,885.64 h50
  text "PA2" at 420.63,838.74 h50
  text "PA1" at 70.63,828.74 h50
  text "PB11" at 1920.63,828.74 h50
  text "PB10" at 2320.63,828.74 h50
  text "TH186B_MG32F02A072_132" at 615.63,813.74 h40
  text "LQFP-80_EV_V11" at 615.63,748.74 h40
  text "2021.05" at 1160.53,745 h35
  text "PA4" at 420.63,738.74 h50
  text "PA3" at 50.63,728.74 h50
  text "PB9" at 1950.63,728.74 h50
  text "PB8" at 2320.63,728.74 h50
  text "PB10" at 1505,705 h50 r90
  text "PA6" at 420.63,638.74 h50
  text "PA5" at 50.63,628.74 h50
  text "PB7" at 1950.63,628.74 h50
  text "PA7" at 465.63,528.74 h50
  text "PB5" at 1870.63,528.74 h50 r90
  text "PA9" at 670.63,523.74 h50 r90
  text "PA11" at 770.63,523.74 h50 r90
  text "PA13" at 870.63,523.74 h50 r90
  text "PA15" at 970.63,523.74 h50 r90
  text "PB1" at 1075.63,523.74 h50 r90
  text "PB3" at 1170.63,523.74 h50 r90
  text "PE1" at 1570.63,523.74 h50 r90
  text "PE3" at 1670.63,523.74 h50 r90
  text "J3 Open : Disable VCP." at 3103.63,318.74 h45
  text "J3 Short : Enable VCP." at 3098.63,233.74 h45
  text "PB0" at 1075.63,168.74 h50 r90
  text "GND" at 1380.63,168.74 h50 r90
  text "PE0" at 1580.63,168.74 h50 r90
  text "PE2" at 1670.63,168.74 h50 r90
  text "PB4" at 1880.63,168.74 h50 r90
  text "PB6" at 1990.63,168.74 h50 r90
  text "PA8" at 670.63,163.74 h50 r90
  text "PB2" at 1170.63,163.74 h50 r90
  text "VDUT" at 1475.63,124.45 h50 r90
  text "PA10" at 770.63,123.74 h50 r90
  text "PA12" at 870.63,123.74 h50 r90
  text "PA14" at 970.63,123.74 h50 r90
Mechanical 1:
  circle w7.88: c3050.63,1008.74 r33
  circle w7.88: c3050.63,1298.74 r25
  circle w7.88: c3050.63,1416.74 r25
  circle w7.88: c3050.63,1503.74 r27
  circle w7.88: c3050.63,1613.74 r27
  lines w7.88: 3028.98,1078.74 3072.28,1078.74 3072.28,1232.74 3028.98,1232.74 3028.98,1078.74
  lines w8.88: 0,0 0,2637.8 3028.98,2637.8 3028.98,1678.74 3072.28,1678.74 3072.28,2637.8 4370.08,2637.8 4370.08,0 3072.28,0 3072.28,938.74 3028.98,938.74 3028.98,0 0,0
Mechanical 2:
  lines w6: 3050.63,1031.74 3050.63,1008.74 3073.63,1008.74 ; 3050.63,1321.74 3050.63,1298.74 3073.63,1298.74 ; 3050.63,1441.74 3050.63,1418.74 3073.63,1418.74 ; 3050.63,1526.74 3050.63,1503.74 3073.63,1503.74 ; 3050.63,1636.74 3050.63,1613.74 3073.63,1613.74
Drill Drawing:
  text ".Legend" at 4450.59,15 h40

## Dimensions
0,0 to 0,2637.8 on Top Overlay
0,0 to 4370.08,0 on Top Overlay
